# Generated by FakeRAM 2.0
VERSION 5.7 ;
BUSBITCHARS "[]" ;
PROPERTYDEFINITIONS
  MACRO width INTEGER ;
  MACRO depth INTEGER ;
  MACRO banks INTEGER ;
END PROPERTYDEFINITIONS
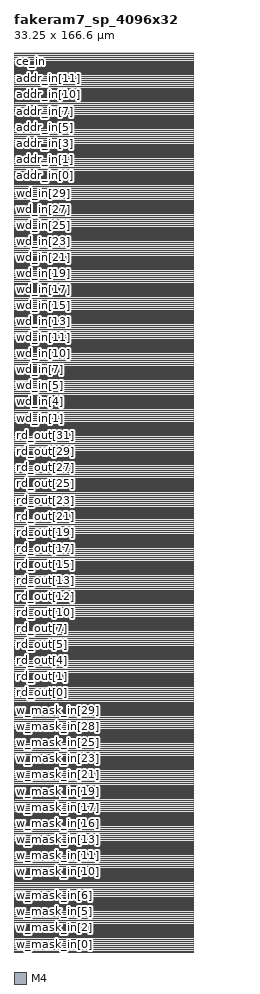
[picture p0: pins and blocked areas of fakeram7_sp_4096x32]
MACRO fakeram7_sp_4096x32
  PROPERTY width 32 ;
  PROPERTY depth 4096 ;
  PROPERTY banks 8 ;
  FOREIGN fakeram7_sp_4096x32 0 0 ;
  SYMMETRY X Y ;
  SIZE 33.250 BY 166.600 ;
  CLASS BLOCK ;
  PIN w_mask_in[0]
    DIRECTION INPUT ;
    USE SIGNAL ;
    SHAPE ABUTMENT ;
    PORT
      LAYER M4 ;
      RECT 0.000 0.048 0.024 0.072 ;
    END
  END w_mask_in[0]
  PIN w_mask_in[1]
    DIRECTION INPUT ;
    USE SIGNAL ;
    SHAPE ABUTMENT ;
    PORT
      LAYER M4 ;
      RECT 0.000 1.536 0.024 1.560 ;
    END
  END w_mask_in[1]
  PIN w_mask_in[2]
    DIRECTION INPUT ;
    USE SIGNAL ;
    SHAPE ABUTMENT ;
    PORT
      LAYER M4 ;
      RECT 0.000 3.024 0.024 3.048 ;
    END
  END w_mask_in[2]
  PIN w_mask_in[3]
    DIRECTION INPUT ;
    USE SIGNAL ;
    SHAPE ABUTMENT ;
    PORT
      LAYER M4 ;
      RECT 0.000 4.512 0.024 4.536 ;
    END
  END w_mask_in[3]
  PIN w_mask_in[4]
    DIRECTION INPUT ;
    USE SIGNAL ;
    SHAPE ABUTMENT ;
    PORT
      LAYER M4 ;
      RECT 0.000 6.000 0.024 6.024 ;
    END
  END w_mask_in[4]
  PIN w_mask_in[5]
    DIRECTION INPUT ;
    USE SIGNAL ;
    SHAPE ABUTMENT ;
    PORT
      LAYER M4 ;
      RECT 0.000 7.488 0.024 7.512 ;
    END
  END w_mask_in[5]
  PIN w_mask_in[6]
    DIRECTION INPUT ;
    USE SIGNAL ;
    SHAPE ABUTMENT ;
    PORT
      LAYER M4 ;
      RECT 0.000 8.976 0.024 9.000 ;
    END
  END w_mask_in[6]
  PIN w_mask_in[7]
    DIRECTION INPUT ;
    USE SIGNAL ;
    SHAPE ABUTMENT ;
    PORT
      LAYER M4 ;
      RECT 0.000 10.464 0.024 10.488 ;
    END
  END w_mask_in[7]
  PIN w_mask_in[8]
    DIRECTION INPUT ;
    USE SIGNAL ;
    SHAPE ABUTMENT ;
    PORT
      LAYER M4 ;
      RECT 0.000 11.952 0.024 11.976 ;
    END
  END w_mask_in[8]
  PIN w_mask_in[9]
    DIRECTION INPUT ;
    USE SIGNAL ;
    SHAPE ABUTMENT ;
    PORT
      LAYER M4 ;
      RECT 0.000 13.440 0.024 13.464 ;
    END
  END w_mask_in[9]
  PIN w_mask_in[10]
    DIRECTION INPUT ;
    USE SIGNAL ;
    SHAPE ABUTMENT ;
    PORT
      LAYER M4 ;
      RECT 0.000 14.928 0.024 14.952 ;
    END
  END w_mask_in[10]
  PIN w_mask_in[11]
    DIRECTION INPUT ;
    USE SIGNAL ;
    SHAPE ABUTMENT ;
    PORT
      LAYER M4 ;
      RECT 0.000 16.416 0.024 16.440 ;
    END
  END w_mask_in[11]
  PIN w_mask_in[12]
    DIRECTION INPUT ;
    USE SIGNAL ;
    SHAPE ABUTMENT ;
    PORT
      LAYER M4 ;
      RECT 0.000 17.904 0.024 17.928 ;
    END
  END w_mask_in[12]
  PIN w_mask_in[13]
    DIRECTION INPUT ;
    USE SIGNAL ;
    SHAPE ABUTMENT ;
    PORT
      LAYER M4 ;
      RECT 0.000 19.392 0.024 19.416 ;
    END
  END w_mask_in[13]
  PIN w_mask_in[14]
    DIRECTION INPUT ;
    USE SIGNAL ;
    SHAPE ABUTMENT ;
    PORT
      LAYER M4 ;
      RECT 0.000 20.880 0.024 20.904 ;
    END
  END w_mask_in[14]
  PIN w_mask_in[15]
    DIRECTION INPUT ;
    USE SIGNAL ;
    SHAPE ABUTMENT ;
    PORT
      LAYER M4 ;
      RECT 0.000 22.368 0.024 22.392 ;
    END
  END w_mask_in[15]
  PIN w_mask_in[16]
    DIRECTION INPUT ;
    USE SIGNAL ;
    SHAPE ABUTMENT ;
    PORT
      LAYER M4 ;
      RECT 0.000 23.856 0.024 23.880 ;
    END
  END w_mask_in[16]
  PIN w_mask_in[17]
    DIRECTION INPUT ;
    USE SIGNAL ;
    SHAPE ABUTMENT ;
    PORT
      LAYER M4 ;
      RECT 0.000 25.344 0.024 25.368 ;
    END
  END w_mask_in[17]
  PIN w_mask_in[18]
    DIRECTION INPUT ;
    USE SIGNAL ;
    SHAPE ABUTMENT ;
    PORT
      LAYER M4 ;
      RECT 0.000 26.832 0.024 26.856 ;
    END
  END w_mask_in[18]
  PIN w_mask_in[19]
    DIRECTION INPUT ;
    USE SIGNAL ;
    SHAPE ABUTMENT ;
    PORT
      LAYER M4 ;
      RECT 0.000 28.320 0.024 28.344 ;
    END
  END w_mask_in[19]
  PIN w_mask_in[20]
    DIRECTION INPUT ;
    USE SIGNAL ;
    SHAPE ABUTMENT ;
    PORT
      LAYER M4 ;
      RECT 0.000 29.808 0.024 29.832 ;
    END
  END w_mask_in[20]
  PIN w_mask_in[21]
    DIRECTION INPUT ;
    USE SIGNAL ;
    SHAPE ABUTMENT ;
    PORT
      LAYER M4 ;
      RECT 0.000 31.296 0.024 31.320 ;
    END
  END w_mask_in[21]
  PIN w_mask_in[22]
    DIRECTION INPUT ;
    USE SIGNAL ;
    SHAPE ABUTMENT ;
    PORT
      LAYER M4 ;
      RECT 0.000 32.784 0.024 32.808 ;
    END
  END w_mask_in[22]
  PIN w_mask_in[23]
    DIRECTION INPUT ;
    USE SIGNAL ;
    SHAPE ABUTMENT ;
    PORT
      LAYER M4 ;
      RECT 0.000 34.272 0.024 34.296 ;
    END
  END w_mask_in[23]
  PIN w_mask_in[24]
    DIRECTION INPUT ;
    USE SIGNAL ;
    SHAPE ABUTMENT ;
    PORT
      LAYER M4 ;
      RECT 0.000 35.760 0.024 35.784 ;
    END
  END w_mask_in[24]
  PIN w_mask_in[25]
    DIRECTION INPUT ;
    USE SIGNAL ;
    SHAPE ABUTMENT ;
    PORT
      LAYER M4 ;
      RECT 0.000 37.248 0.024 37.272 ;
    END
  END w_mask_in[25]
  PIN w_mask_in[26]
    DIRECTION INPUT ;
    USE SIGNAL ;
    SHAPE ABUTMENT ;
    PORT
      LAYER M4 ;
      RECT 0.000 38.736 0.024 38.760 ;
    END
  END w_mask_in[26]
  PIN w_mask_in[27]
    DIRECTION INPUT ;
    USE SIGNAL ;
    SHAPE ABUTMENT ;
    PORT
      LAYER M4 ;
      RECT 0.000 40.224 0.024 40.248 ;
    END
  END w_mask_in[27]
  PIN w_mask_in[28]
    DIRECTION INPUT ;
    USE SIGNAL ;
    SHAPE ABUTMENT ;
    PORT
      LAYER M4 ;
      RECT 0.000 41.712 0.024 41.736 ;
    END
  END w_mask_in[28]
  PIN w_mask_in[29]
    DIRECTION INPUT ;
    USE SIGNAL ;
    SHAPE ABUTMENT ;
    PORT
      LAYER M4 ;
      RECT 0.000 43.200 0.024 43.224 ;
    END
  END w_mask_in[29]
  PIN w_mask_in[30]
    DIRECTION INPUT ;
    USE SIGNAL ;
    SHAPE ABUTMENT ;
    PORT
      LAYER M4 ;
      RECT 0.000 44.688 0.024 44.712 ;
    END
  END w_mask_in[30]
  PIN w_mask_in[31]
    DIRECTION INPUT ;
    USE SIGNAL ;
    SHAPE ABUTMENT ;
    PORT
      LAYER M4 ;
      RECT 0.000 46.176 0.024 46.200 ;
    END
  END w_mask_in[31]
  PIN rd_out[0]
    DIRECTION OUTPUT ;
    USE SIGNAL ;
    SHAPE ABUTMENT ;
    PORT
      LAYER M4 ;
      RECT 0.000 47.952 0.024 47.976 ;
    END
  END rd_out[0]
  PIN rd_out[1]
    DIRECTION OUTPUT ;
    USE SIGNAL ;
    SHAPE ABUTMENT ;
    PORT
      LAYER M4 ;
      RECT 0.000 49.440 0.024 49.464 ;
    END
  END rd_out[1]
  PIN rd_out[2]
    DIRECTION OUTPUT ;
    USE SIGNAL ;
    SHAPE ABUTMENT ;
    PORT
      LAYER M4 ;
      RECT 0.000 50.928 0.024 50.952 ;
    END
  END rd_out[2]
  PIN rd_out[3]
    DIRECTION OUTPUT ;
    USE SIGNAL ;
    SHAPE ABUTMENT ;
    PORT
      LAYER M4 ;
      RECT 0.000 52.416 0.024 52.440 ;
    END
  END rd_out[3]
  PIN rd_out[4]
    DIRECTION OUTPUT ;
    USE SIGNAL ;
    SHAPE ABUTMENT ;
    PORT
      LAYER M4 ;
      RECT 0.000 53.904 0.024 53.928 ;
    END
  END rd_out[4]
  PIN rd_out[5]
    DIRECTION OUTPUT ;
    USE SIGNAL ;
    SHAPE ABUTMENT ;
    PORT
      LAYER M4 ;
      RECT 0.000 55.392 0.024 55.416 ;
    END
  END rd_out[5]
  PIN rd_out[6]
    DIRECTION OUTPUT ;
    USE SIGNAL ;
    SHAPE ABUTMENT ;
    PORT
      LAYER M4 ;
      RECT 0.000 56.880 0.024 56.904 ;
    END
  END rd_out[6]
  PIN rd_out[7]
    DIRECTION OUTPUT ;
    USE SIGNAL ;
    SHAPE ABUTMENT ;
    PORT
      LAYER M4 ;
      RECT 0.000 58.368 0.024 58.392 ;
    END
  END rd_out[7]
  PIN rd_out[8]
    DIRECTION OUTPUT ;
    USE SIGNAL ;
    SHAPE ABUTMENT ;
    PORT
      LAYER M4 ;
      RECT 0.000 59.856 0.024 59.880 ;
    END
  END rd_out[8]
  PIN rd_out[9]
    DIRECTION OUTPUT ;
    USE SIGNAL ;
    SHAPE ABUTMENT ;
    PORT
      LAYER M4 ;
      RECT 0.000 61.344 0.024 61.368 ;
    END
  END rd_out[9]
  PIN rd_out[10]
    DIRECTION OUTPUT ;
    USE SIGNAL ;
    SHAPE ABUTMENT ;
    PORT
      LAYER M4 ;
      RECT 0.000 62.832 0.024 62.856 ;
    END
  END rd_out[10]
  PIN rd_out[11]
    DIRECTION OUTPUT ;
    USE SIGNAL ;
    SHAPE ABUTMENT ;
    PORT
      LAYER M4 ;
      RECT 0.000 64.320 0.024 64.344 ;
    END
  END rd_out[11]
  PIN rd_out[12]
    DIRECTION OUTPUT ;
    USE SIGNAL ;
    SHAPE ABUTMENT ;
    PORT
      LAYER M4 ;
      RECT 0.000 65.808 0.024 65.832 ;
    END
  END rd_out[12]
  PIN rd_out[13]
    DIRECTION OUTPUT ;
    USE SIGNAL ;
    SHAPE ABUTMENT ;
    PORT
      LAYER M4 ;
      RECT 0.000 67.296 0.024 67.320 ;
    END
  END rd_out[13]
  PIN rd_out[14]
    DIRECTION OUTPUT ;
    USE SIGNAL ;
    SHAPE ABUTMENT ;
    PORT
      LAYER M4 ;
      RECT 0.000 68.784 0.024 68.808 ;
    END
  END rd_out[14]
  PIN rd_out[15]
    DIRECTION OUTPUT ;
    USE SIGNAL ;
    SHAPE ABUTMENT ;
    PORT
      LAYER M4 ;
      RECT 0.000 70.272 0.024 70.296 ;
    END
  END rd_out[15]
  PIN rd_out[16]
    DIRECTION OUTPUT ;
    USE SIGNAL ;
    SHAPE ABUTMENT ;
    PORT
      LAYER M4 ;
      RECT 0.000 71.760 0.024 71.784 ;
    END
  END rd_out[16]
  PIN rd_out[17]
    DIRECTION OUTPUT ;
    USE SIGNAL ;
    SHAPE ABUTMENT ;
    PORT
      LAYER M4 ;
      RECT 0.000 73.248 0.024 73.272 ;
    END
  END rd_out[17]
  PIN rd_out[18]
    DIRECTION OUTPUT ;
    USE SIGNAL ;
    SHAPE ABUTMENT ;
    PORT
      LAYER M4 ;
      RECT 0.000 74.736 0.024 74.760 ;
    END
  END rd_out[18]
  PIN rd_out[19]
    DIRECTION OUTPUT ;
    USE SIGNAL ;
    SHAPE ABUTMENT ;
    PORT
      LAYER M4 ;
      RECT 0.000 76.224 0.024 76.248 ;
    END
  END rd_out[19]
  PIN rd_out[20]
    DIRECTION OUTPUT ;
    USE SIGNAL ;
    SHAPE ABUTMENT ;
    PORT
      LAYER M4 ;
      RECT 0.000 77.712 0.024 77.736 ;
    END
  END rd_out[20]
  PIN rd_out[21]
    DIRECTION OUTPUT ;
    USE SIGNAL ;
    SHAPE ABUTMENT ;
    PORT
      LAYER M4 ;
      RECT 0.000 79.200 0.024 79.224 ;
    END
  END rd_out[21]
  PIN rd_out[22]
    DIRECTION OUTPUT ;
    USE SIGNAL ;
    SHAPE ABUTMENT ;
    PORT
      LAYER M4 ;
      RECT 0.000 80.688 0.024 80.712 ;
    END
  END rd_out[22]
  PIN rd_out[23]
    DIRECTION OUTPUT ;
    USE SIGNAL ;
    SHAPE ABUTMENT ;
    PORT
      LAYER M4 ;
      RECT 0.000 82.176 0.024 82.200 ;
    END
  END rd_out[23]
  PIN rd_out[24]
    DIRECTION OUTPUT ;
    USE SIGNAL ;
    SHAPE ABUTMENT ;
    PORT
      LAYER M4 ;
      RECT 0.000 83.664 0.024 83.688 ;
    END
  END rd_out[24]
  PIN rd_out[25]
    DIRECTION OUTPUT ;
    USE SIGNAL ;
    SHAPE ABUTMENT ;
    PORT
      LAYER M4 ;
      RECT 0.000 85.152 0.024 85.176 ;
    END
  END rd_out[25]
  PIN rd_out[26]
    DIRECTION OUTPUT ;
    USE SIGNAL ;
    SHAPE ABUTMENT ;
    PORT
      LAYER M4 ;
      RECT 0.000 86.640 0.024 86.664 ;
    END
  END rd_out[26]
  PIN rd_out[27]
    DIRECTION OUTPUT ;
    USE SIGNAL ;
    SHAPE ABUTMENT ;
    PORT
      LAYER M4 ;
      RECT 0.000 88.128 0.024 88.152 ;
    END
  END rd_out[27]
  PIN rd_out[28]
    DIRECTION OUTPUT ;
    USE SIGNAL ;
    SHAPE ABUTMENT ;
    PORT
      LAYER M4 ;
      RECT 0.000 89.616 0.024 89.640 ;
    END
  END rd_out[28]
  PIN rd_out[29]
    DIRECTION OUTPUT ;
    USE SIGNAL ;
    SHAPE ABUTMENT ;
    PORT
      LAYER M4 ;
      RECT 0.000 91.104 0.024 91.128 ;
    END
  END rd_out[29]
  PIN rd_out[30]
    DIRECTION OUTPUT ;
    USE SIGNAL ;
    SHAPE ABUTMENT ;
    PORT
      LAYER M4 ;
      RECT 0.000 92.592 0.024 92.616 ;
    END
  END rd_out[30]
  PIN rd_out[31]
    DIRECTION OUTPUT ;
    USE SIGNAL ;
    SHAPE ABUTMENT ;
    PORT
      LAYER M4 ;
      RECT 0.000 94.080 0.024 94.104 ;
    END
  END rd_out[31]
  PIN wd_in[0]
    DIRECTION INPUT ;
    USE SIGNAL ;
    SHAPE ABUTMENT ;
    PORT
      LAYER M4 ;
      RECT 0.000 95.856 0.024 95.880 ;
    END
  END wd_in[0]
  PIN wd_in[1]
    DIRECTION INPUT ;
    USE SIGNAL ;
    SHAPE ABUTMENT ;
    PORT
      LAYER M4 ;
      RECT 0.000 97.344 0.024 97.368 ;
    END
  END wd_in[1]
  PIN wd_in[2]
    DIRECTION INPUT ;
    USE SIGNAL ;
    SHAPE ABUTMENT ;
    PORT
      LAYER M4 ;
      RECT 0.000 98.832 0.024 98.856 ;
    END
  END wd_in[2]
  PIN wd_in[3]
    DIRECTION INPUT ;
    USE SIGNAL ;
    SHAPE ABUTMENT ;
    PORT
      LAYER M4 ;
      RECT 0.000 100.320 0.024 100.344 ;
    END
  END wd_in[3]
  PIN wd_in[4]
    DIRECTION INPUT ;
    USE SIGNAL ;
    SHAPE ABUTMENT ;
    PORT
      LAYER M4 ;
      RECT 0.000 101.808 0.024 101.832 ;
    END
  END wd_in[4]
  PIN wd_in[5]
    DIRECTION INPUT ;
    USE SIGNAL ;
    SHAPE ABUTMENT ;
    PORT
      LAYER M4 ;
      RECT 0.000 103.296 0.024 103.320 ;
    END
  END wd_in[5]
  PIN wd_in[6]
    DIRECTION INPUT ;
    USE SIGNAL ;
    SHAPE ABUTMENT ;
    PORT
      LAYER M4 ;
      RECT 0.000 104.784 0.024 104.808 ;
    END
  END wd_in[6]
  PIN wd_in[7]
    DIRECTION INPUT ;
    USE SIGNAL ;
    SHAPE ABUTMENT ;
    PORT
      LAYER M4 ;
      RECT 0.000 106.272 0.024 106.296 ;
    END
  END wd_in[7]
  PIN wd_in[8]
    DIRECTION INPUT ;
    USE SIGNAL ;
    SHAPE ABUTMENT ;
    PORT
      LAYER M4 ;
      RECT 0.000 107.760 0.024 107.784 ;
    END
  END wd_in[8]
  PIN wd_in[9]
    DIRECTION INPUT ;
    USE SIGNAL ;
    SHAPE ABUTMENT ;
    PORT
      LAYER M4 ;
      RECT 0.000 109.248 0.024 109.272 ;
    END
  END wd_in[9]
  PIN wd_in[10]
    DIRECTION INPUT ;
    USE SIGNAL ;
    SHAPE ABUTMENT ;
    PORT
      LAYER M4 ;
      RECT 0.000 110.736 0.024 110.760 ;
    END
  END wd_in[10]
  PIN wd_in[11]
    DIRECTION INPUT ;
    USE SIGNAL ;
    SHAPE ABUTMENT ;
    PORT
      LAYER M4 ;
      RECT 0.000 112.224 0.024 112.248 ;
    END
  END wd_in[11]
  PIN wd_in[12]
    DIRECTION INPUT ;
    USE SIGNAL ;
    SHAPE ABUTMENT ;
    PORT
      LAYER M4 ;
      RECT 0.000 113.712 0.024 113.736 ;
    END
  END wd_in[12]
  PIN wd_in[13]
    DIRECTION INPUT ;
    USE SIGNAL ;
    SHAPE ABUTMENT ;
    PORT
      LAYER M4 ;
      RECT 0.000 115.200 0.024 115.224 ;
    END
  END wd_in[13]
  PIN wd_in[14]
    DIRECTION INPUT ;
    USE SIGNAL ;
    SHAPE ABUTMENT ;
    PORT
      LAYER M4 ;
      RECT 0.000 116.688 0.024 116.712 ;
    END
  END wd_in[14]
  PIN wd_in[15]
    DIRECTION INPUT ;
    USE SIGNAL ;
    SHAPE ABUTMENT ;
    PORT
      LAYER M4 ;
      RECT 0.000 118.176 0.024 118.200 ;
    END
  END wd_in[15]
  PIN wd_in[16]
    DIRECTION INPUT ;
    USE SIGNAL ;
    SHAPE ABUTMENT ;
    PORT
      LAYER M4 ;
      RECT 0.000 119.664 0.024 119.688 ;
    END
  END wd_in[16]
  PIN wd_in[17]
    DIRECTION INPUT ;
    USE SIGNAL ;
    SHAPE ABUTMENT ;
    PORT
      LAYER M4 ;
      RECT 0.000 121.152 0.024 121.176 ;
    END
  END wd_in[17]
  PIN wd_in[18]
    DIRECTION INPUT ;
    USE SIGNAL ;
    SHAPE ABUTMENT ;
    PORT
      LAYER M4 ;
      RECT 0.000 122.640 0.024 122.664 ;
    END
  END wd_in[18]
  PIN wd_in[19]
    DIRECTION INPUT ;
    USE SIGNAL ;
    SHAPE ABUTMENT ;
    PORT
      LAYER M4 ;
      RECT 0.000 124.128 0.024 124.152 ;
    END
  END wd_in[19]
  PIN wd_in[20]
    DIRECTION INPUT ;
    USE SIGNAL ;
    SHAPE ABUTMENT ;
    PORT
      LAYER M4 ;
      RECT 0.000 125.616 0.024 125.640 ;
    END
  END wd_in[20]
  PIN wd_in[21]
    DIRECTION INPUT ;
    USE SIGNAL ;
    SHAPE ABUTMENT ;
    PORT
      LAYER M4 ;
      RECT 0.000 127.104 0.024 127.128 ;
    END
  END wd_in[21]
  PIN wd_in[22]
    DIRECTION INPUT ;
    USE SIGNAL ;
    SHAPE ABUTMENT ;
    PORT
      LAYER M4 ;
      RECT 0.000 128.592 0.024 128.616 ;
    END
  END wd_in[22]
  PIN wd_in[23]
    DIRECTION INPUT ;
    USE SIGNAL ;
    SHAPE ABUTMENT ;
    PORT
      LAYER M4 ;
      RECT 0.000 130.080 0.024 130.104 ;
    END
  END wd_in[23]
  PIN wd_in[24]
    DIRECTION INPUT ;
    USE SIGNAL ;
    SHAPE ABUTMENT ;
    PORT
      LAYER M4 ;
      RECT 0.000 131.568 0.024 131.592 ;
    END
  END wd_in[24]
  PIN wd_in[25]
    DIRECTION INPUT ;
    USE SIGNAL ;
    SHAPE ABUTMENT ;
    PORT
      LAYER M4 ;
      RECT 0.000 133.056 0.024 133.080 ;
    END
  END wd_in[25]
  PIN wd_in[26]
    DIRECTION INPUT ;
    USE SIGNAL ;
    SHAPE ABUTMENT ;
    PORT
      LAYER M4 ;
      RECT 0.000 134.544 0.024 134.568 ;
    END
  END wd_in[26]
  PIN wd_in[27]
    DIRECTION INPUT ;
    USE SIGNAL ;
    SHAPE ABUTMENT ;
    PORT
      LAYER M4 ;
      RECT 0.000 136.032 0.024 136.056 ;
    END
  END wd_in[27]
  PIN wd_in[28]
    DIRECTION INPUT ;
    USE SIGNAL ;
    SHAPE ABUTMENT ;
    PORT
      LAYER M4 ;
      RECT 0.000 137.520 0.024 137.544 ;
    END
  END wd_in[28]
  PIN wd_in[29]
    DIRECTION INPUT ;
    USE SIGNAL ;
    SHAPE ABUTMENT ;
    PORT
      LAYER M4 ;
      RECT 0.000 139.008 0.024 139.032 ;
    END
  END wd_in[29]
  PIN wd_in[30]
    DIRECTION INPUT ;
    USE SIGNAL ;
    SHAPE ABUTMENT ;
    PORT
      LAYER M4 ;
      RECT 0.000 140.496 0.024 140.520 ;
    END
  END wd_in[30]
  PIN wd_in[31]
    DIRECTION INPUT ;
    USE SIGNAL ;
    SHAPE ABUTMENT ;
    PORT
      LAYER M4 ;
      RECT 0.000 141.984 0.024 142.008 ;
    END
  END wd_in[31]
  PIN addr_in[0]
    DIRECTION INPUT ;
    USE SIGNAL ;
    SHAPE ABUTMENT ;
    PORT
      LAYER M4 ;
      RECT 0.000 143.760 0.024 143.784 ;
    END
  END addr_in[0]
  PIN addr_in[1]
    DIRECTION INPUT ;
    USE SIGNAL ;
    SHAPE ABUTMENT ;
    PORT
      LAYER M4 ;
      RECT 0.000 145.248 0.024 145.272 ;
    END
  END addr_in[1]
  PIN addr_in[2]
    DIRECTION INPUT ;
    USE SIGNAL ;
    SHAPE ABUTMENT ;
    PORT
      LAYER M4 ;
      RECT 0.000 146.736 0.024 146.760 ;
    END
  END addr_in[2]
  PIN addr_in[3]
    DIRECTION INPUT ;
    USE SIGNAL ;
    SHAPE ABUTMENT ;
    PORT
      LAYER M4 ;
      RECT 0.000 148.224 0.024 148.248 ;
    END
  END addr_in[3]
  PIN addr_in[4]
    DIRECTION INPUT ;
    USE SIGNAL ;
    SHAPE ABUTMENT ;
    PORT
      LAYER M4 ;
      RECT 0.000 149.712 0.024 149.736 ;
    END
  END addr_in[4]
  PIN addr_in[5]
    DIRECTION INPUT ;
    USE SIGNAL ;
    SHAPE ABUTMENT ;
    PORT
      LAYER M4 ;
      RECT 0.000 151.200 0.024 151.224 ;
    END
  END addr_in[5]
  PIN addr_in[6]
    DIRECTION INPUT ;
    USE SIGNAL ;
    SHAPE ABUTMENT ;
    PORT
      LAYER M4 ;
      RECT 0.000 152.688 0.024 152.712 ;
    END
  END addr_in[6]
  PIN addr_in[7]
    DIRECTION INPUT ;
    USE SIGNAL ;
    SHAPE ABUTMENT ;
    PORT
      LAYER M4 ;
      RECT 0.000 154.176 0.024 154.200 ;
    END
  END addr_in[7]
  PIN addr_in[8]
    DIRECTION INPUT ;
    USE SIGNAL ;
    SHAPE ABUTMENT ;
    PORT
      LAYER M4 ;
      RECT 0.000 155.664 0.024 155.688 ;
    END
  END addr_in[8]
  PIN addr_in[9]
    DIRECTION INPUT ;
    USE SIGNAL ;
    SHAPE ABUTMENT ;
    PORT
      LAYER M4 ;
      RECT 0.000 157.152 0.024 157.176 ;
    END
  END addr_in[9]
  PIN addr_in[10]
    DIRECTION INPUT ;
    USE SIGNAL ;
    SHAPE ABUTMENT ;
    PORT
      LAYER M4 ;
      RECT 0.000 158.640 0.024 158.664 ;
    END
  END addr_in[10]
  PIN addr_in[11]
    DIRECTION INPUT ;
    USE SIGNAL ;
    SHAPE ABUTMENT ;
    PORT
      LAYER M4 ;
      RECT 0.000 160.128 0.024 160.152 ;
    END
  END addr_in[11]
  PIN we_in
    DIRECTION INPUT ;
    USE SIGNAL ;
    SHAPE ABUTMENT ;
    PORT
      LAYER M4 ;
      RECT 0.000 161.904 0.024 161.928 ;
    END
  END we_in
  PIN ce_in
    DIRECTION INPUT ;
    USE SIGNAL ;
    SHAPE ABUTMENT ;
    PORT
      LAYER M4 ;
      RECT 0.000 163.392 0.024 163.416 ;
    END
  END ce_in
  PIN clk
    DIRECTION INPUT ;
    USE SIGNAL ;
    SHAPE ABUTMENT ;
    PORT
      LAYER M4 ;
      RECT 0.000 164.880 0.024 164.904 ;
    END
  END clk
  PIN VSS
    DIRECTION INOUT ;
    USE GROUND ;
    PORT
      LAYER M4 ;
      RECT 0.048 0.000 33.202 0.096 ;
      RECT 0.048 0.768 33.202 0.864 ;
      RECT 0.048 1.536 33.202 1.632 ;
      RECT 0.048 2.304 33.202 2.400 ;
      RECT 0.048 3.072 33.202 3.168 ;
      RECT 0.048 3.840 33.202 3.936 ;
      RECT 0.048 4.608 33.202 4.704 ;
      RECT 0.048 5.376 33.202 5.472 ;
      RECT 0.048 6.144 33.202 6.240 ;
      RECT 0.048 6.912 33.202 7.008 ;
      RECT 0.048 7.680 33.202 7.776 ;
      RECT 0.048 8.448 33.202 8.544 ;
      RECT 0.048 9.216 33.202 9.312 ;
      RECT 0.048 9.984 33.202 10.080 ;
      RECT 0.048 10.752 33.202 10.848 ;
      RECT 0.048 11.520 33.202 11.616 ;
      RECT 0.048 12.288 33.202 12.384 ;
      RECT 0.048 13.056 33.202 13.152 ;
      RECT 0.048 13.824 33.202 13.920 ;
      RECT 0.048 14.592 33.202 14.688 ;
      RECT 0.048 15.360 33.202 15.456 ;
      RECT 0.048 16.128 33.202 16.224 ;
      RECT 0.048 16.896 33.202 16.992 ;
      RECT 0.048 17.664 33.202 17.760 ;
      RECT 0.048 18.432 33.202 18.528 ;
      RECT 0.048 19.200 33.202 19.296 ;
      RECT 0.048 19.968 33.202 20.064 ;
      RECT 0.048 20.736 33.202 20.832 ;
      RECT 0.048 21.504 33.202 21.600 ;
      RECT 0.048 22.272 33.202 22.368 ;
      RECT 0.048 23.040 33.202 23.136 ;
      RECT 0.048 23.808 33.202 23.904 ;
      RECT 0.048 24.576 33.202 24.672 ;
      RECT 0.048 25.344 33.202 25.440 ;
      RECT 0.048 26.112 33.202 26.208 ;
      RECT 0.048 26.880 33.202 26.976 ;
      RECT 0.048 27.648 33.202 27.744 ;
      RECT 0.048 28.416 33.202 28.512 ;
      RECT 0.048 29.184 33.202 29.280 ;
      RECT 0.048 29.952 33.202 30.048 ;
      RECT 0.048 30.720 33.202 30.816 ;
      RECT 0.048 31.488 33.202 31.584 ;
      RECT 0.048 32.256 33.202 32.352 ;
      RECT 0.048 33.024 33.202 33.120 ;
      RECT 0.048 33.792 33.202 33.888 ;
      RECT 0.048 34.560 33.202 34.656 ;
      RECT 0.048 35.328 33.202 35.424 ;
      RECT 0.048 36.096 33.202 36.192 ;
      RECT 0.048 36.864 33.202 36.960 ;
      RECT 0.048 37.632 33.202 37.728 ;
      RECT 0.048 38.400 33.202 38.496 ;
      RECT 0.048 39.168 33.202 39.264 ;
      RECT 0.048 39.936 33.202 40.032 ;
      RECT 0.048 40.704 33.202 40.800 ;
      RECT 0.048 41.472 33.202 41.568 ;
      RECT 0.048 42.240 33.202 42.336 ;
      RECT 0.048 43.008 33.202 43.104 ;
      RECT 0.048 43.776 33.202 43.872 ;
      RECT 0.048 44.544 33.202 44.640 ;
      RECT 0.048 45.312 33.202 45.408 ;
      RECT 0.048 46.080 33.202 46.176 ;
      RECT 0.048 46.848 33.202 46.944 ;
      RECT 0.048 47.616 33.202 47.712 ;
      RECT 0.048 48.384 33.202 48.480 ;
      RECT 0.048 49.152 33.202 49.248 ;
      RECT 0.048 49.920 33.202 50.016 ;
      RECT 0.048 50.688 33.202 50.784 ;
      RECT 0.048 51.456 33.202 51.552 ;
      RECT 0.048 52.224 33.202 52.320 ;
      RECT 0.048 52.992 33.202 53.088 ;
      RECT 0.048 53.760 33.202 53.856 ;
      RECT 0.048 54.528 33.202 54.624 ;
      RECT 0.048 55.296 33.202 55.392 ;
      RECT 0.048 56.064 33.202 56.160 ;
      RECT 0.048 56.832 33.202 56.928 ;
      RECT 0.048 57.600 33.202 57.696 ;
      RECT 0.048 58.368 33.202 58.464 ;
      RECT 0.048 59.136 33.202 59.232 ;
      RECT 0.048 59.904 33.202 60.000 ;
      RECT 0.048 60.672 33.202 60.768 ;
      RECT 0.048 61.440 33.202 61.536 ;
      RECT 0.048 62.208 33.202 62.304 ;
      RECT 0.048 62.976 33.202 63.072 ;
      RECT 0.048 63.744 33.202 63.840 ;
      RECT 0.048 64.512 33.202 64.608 ;
      RECT 0.048 65.280 33.202 65.376 ;
      RECT 0.048 66.048 33.202 66.144 ;
      RECT 0.048 66.816 33.202 66.912 ;
      RECT 0.048 67.584 33.202 67.680 ;
      RECT 0.048 68.352 33.202 68.448 ;
      RECT 0.048 69.120 33.202 69.216 ;
      RECT 0.048 69.888 33.202 69.984 ;
      RECT 0.048 70.656 33.202 70.752 ;
      RECT 0.048 71.424 33.202 71.520 ;
      RECT 0.048 72.192 33.202 72.288 ;
      RECT 0.048 72.960 33.202 73.056 ;
      RECT 0.048 73.728 33.202 73.824 ;
      RECT 0.048 74.496 33.202 74.592 ;
      RECT 0.048 75.264 33.202 75.360 ;
      RECT 0.048 76.032 33.202 76.128 ;
      RECT 0.048 76.800 33.202 76.896 ;
      RECT 0.048 77.568 33.202 77.664 ;
      RECT 0.048 78.336 33.202 78.432 ;
      RECT 0.048 79.104 33.202 79.200 ;
      RECT 0.048 79.872 33.202 79.968 ;
      RECT 0.048 80.640 33.202 80.736 ;
      RECT 0.048 81.408 33.202 81.504 ;
      RECT 0.048 82.176 33.202 82.272 ;
      RECT 0.048 82.944 33.202 83.040 ;
      RECT 0.048 83.712 33.202 83.808 ;
      RECT 0.048 84.480 33.202 84.576 ;
      RECT 0.048 85.248 33.202 85.344 ;
      RECT 0.048 86.016 33.202 86.112 ;
      RECT 0.048 86.784 33.202 86.880 ;
      RECT 0.048 87.552 33.202 87.648 ;
      RECT 0.048 88.320 33.202 88.416 ;
      RECT 0.048 89.088 33.202 89.184 ;
      RECT 0.048 89.856 33.202 89.952 ;
      RECT 0.048 90.624 33.202 90.720 ;
      RECT 0.048 91.392 33.202 91.488 ;
      RECT 0.048 92.160 33.202 92.256 ;
      RECT 0.048 92.928 33.202 93.024 ;
      RECT 0.048 93.696 33.202 93.792 ;
      RECT 0.048 94.464 33.202 94.560 ;
      RECT 0.048 95.232 33.202 95.328 ;
      RECT 0.048 96.000 33.202 96.096 ;
      RECT 0.048 96.768 33.202 96.864 ;
      RECT 0.048 97.536 33.202 97.632 ;
      RECT 0.048 98.304 33.202 98.400 ;
      RECT 0.048 99.072 33.202 99.168 ;
      RECT 0.048 99.840 33.202 99.936 ;
      RECT 0.048 100.608 33.202 100.704 ;
      RECT 0.048 101.376 33.202 101.472 ;
      RECT 0.048 102.144 33.202 102.240 ;
      RECT 0.048 102.912 33.202 103.008 ;
      RECT 0.048 103.680 33.202 103.776 ;
      RECT 0.048 104.448 33.202 104.544 ;
      RECT 0.048 105.216 33.202 105.312 ;
      RECT 0.048 105.984 33.202 106.080 ;
      RECT 0.048 106.752 33.202 106.848 ;
      RECT 0.048 107.520 33.202 107.616 ;
      RECT 0.048 108.288 33.202 108.384 ;
      RECT 0.048 109.056 33.202 109.152 ;
      RECT 0.048 109.824 33.202 109.920 ;
      RECT 0.048 110.592 33.202 110.688 ;
      RECT 0.048 111.360 33.202 111.456 ;
      RECT 0.048 112.128 33.202 112.224 ;
      RECT 0.048 112.896 33.202 112.992 ;
      RECT 0.048 113.664 33.202 113.760 ;
      RECT 0.048 114.432 33.202 114.528 ;
      RECT 0.048 115.200 33.202 115.296 ;
      RECT 0.048 115.968 33.202 116.064 ;
      RECT 0.048 116.736 33.202 116.832 ;
      RECT 0.048 117.504 33.202 117.600 ;
      RECT 0.048 118.272 33.202 118.368 ;
      RECT 0.048 119.040 33.202 119.136 ;
      RECT 0.048 119.808 33.202 119.904 ;
      RECT 0.048 120.576 33.202 120.672 ;
      RECT 0.048 121.344 33.202 121.440 ;
      RECT 0.048 122.112 33.202 122.208 ;
      RECT 0.048 122.880 33.202 122.976 ;
      RECT 0.048 123.648 33.202 123.744 ;
      RECT 0.048 124.416 33.202 124.512 ;
      RECT 0.048 125.184 33.202 125.280 ;
      RECT 0.048 125.952 33.202 126.048 ;
      RECT 0.048 126.720 33.202 126.816 ;
      RECT 0.048 127.488 33.202 127.584 ;
      RECT 0.048 128.256 33.202 128.352 ;
      RECT 0.048 129.024 33.202 129.120 ;
      RECT 0.048 129.792 33.202 129.888 ;
      RECT 0.048 130.560 33.202 130.656 ;
      RECT 0.048 131.328 33.202 131.424 ;
      RECT 0.048 132.096 33.202 132.192 ;
      RECT 0.048 132.864 33.202 132.960 ;
      RECT 0.048 133.632 33.202 133.728 ;
      RECT 0.048 134.400 33.202 134.496 ;
      RECT 0.048 135.168 33.202 135.264 ;
      RECT 0.048 135.936 33.202 136.032 ;
      RECT 0.048 136.704 33.202 136.800 ;
      RECT 0.048 137.472 33.202 137.568 ;
      RECT 0.048 138.240 33.202 138.336 ;
      RECT 0.048 139.008 33.202 139.104 ;
      RECT 0.048 139.776 33.202 139.872 ;
      RECT 0.048 140.544 33.202 140.640 ;
      RECT 0.048 141.312 33.202 141.408 ;
      RECT 0.048 142.080 33.202 142.176 ;
      RECT 0.048 142.848 33.202 142.944 ;
      RECT 0.048 143.616 33.202 143.712 ;
      RECT 0.048 144.384 33.202 144.480 ;
      RECT 0.048 145.152 33.202 145.248 ;
      RECT 0.048 145.920 33.202 146.016 ;
      RECT 0.048 146.688 33.202 146.784 ;
      RECT 0.048 147.456 33.202 147.552 ;
      RECT 0.048 148.224 33.202 148.320 ;
      RECT 0.048 148.992 33.202 149.088 ;
      RECT 0.048 149.760 33.202 149.856 ;
      RECT 0.048 150.528 33.202 150.624 ;
      RECT 0.048 151.296 33.202 151.392 ;
      RECT 0.048 152.064 33.202 152.160 ;
      RECT 0.048 152.832 33.202 152.928 ;
      RECT 0.048 153.600 33.202 153.696 ;
      RECT 0.048 154.368 33.202 154.464 ;
      RECT 0.048 155.136 33.202 155.232 ;
      RECT 0.048 155.904 33.202 156.000 ;
      RECT 0.048 156.672 33.202 156.768 ;
      RECT 0.048 157.440 33.202 157.536 ;
      RECT 0.048 158.208 33.202 158.304 ;
      RECT 0.048 158.976 33.202 159.072 ;
      RECT 0.048 159.744 33.202 159.840 ;
      RECT 0.048 160.512 33.202 160.608 ;
      RECT 0.048 161.280 33.202 161.376 ;
      RECT 0.048 162.048 33.202 162.144 ;
      RECT 0.048 162.816 33.202 162.912 ;
      RECT 0.048 163.584 33.202 163.680 ;
      RECT 0.048 164.352 33.202 164.448 ;
      RECT 0.048 165.120 33.202 165.216 ;
      RECT 0.048 165.888 33.202 165.984 ;
    END
  END VSS
  PIN VDD
    DIRECTION INOUT ;
    USE POWER ;
    PORT
      LAYER M4 ;
      RECT 0.048 0.384 33.202 0.480 ;
      RECT 0.048 1.152 33.202 1.248 ;
      RECT 0.048 1.920 33.202 2.016 ;
      RECT 0.048 2.688 33.202 2.784 ;
      RECT 0.048 3.456 33.202 3.552 ;
      RECT 0.048 4.224 33.202 4.320 ;
      RECT 0.048 4.992 33.202 5.088 ;
      RECT 0.048 5.760 33.202 5.856 ;
      RECT 0.048 6.528 33.202 6.624 ;
      RECT 0.048 7.296 33.202 7.392 ;
      RECT 0.048 8.064 33.202 8.160 ;
      RECT 0.048 8.832 33.202 8.928 ;
      RECT 0.048 9.600 33.202 9.696 ;
      RECT 0.048 10.368 33.202 10.464 ;
      RECT 0.048 11.136 33.202 11.232 ;
      RECT 0.048 11.904 33.202 12.000 ;
      RECT 0.048 12.672 33.202 12.768 ;
      RECT 0.048 13.440 33.202 13.536 ;
      RECT 0.048 14.208 33.202 14.304 ;
      RECT 0.048 14.976 33.202 15.072 ;
      RECT 0.048 15.744 33.202 15.840 ;
      RECT 0.048 16.512 33.202 16.608 ;
      RECT 0.048 17.280 33.202 17.376 ;
      RECT 0.048 18.048 33.202 18.144 ;
      RECT 0.048 18.816 33.202 18.912 ;
      RECT 0.048 19.584 33.202 19.680 ;
      RECT 0.048 20.352 33.202 20.448 ;
      RECT 0.048 21.120 33.202 21.216 ;
      RECT 0.048 21.888 33.202 21.984 ;
      RECT 0.048 22.656 33.202 22.752 ;
      RECT 0.048 23.424 33.202 23.520 ;
      RECT 0.048 24.192 33.202 24.288 ;
      RECT 0.048 24.960 33.202 25.056 ;
      RECT 0.048 25.728 33.202 25.824 ;
      RECT 0.048 26.496 33.202 26.592 ;
      RECT 0.048 27.264 33.202 27.360 ;
      RECT 0.048 28.032 33.202 28.128 ;
      RECT 0.048 28.800 33.202 28.896 ;
      RECT 0.048 29.568 33.202 29.664 ;
      RECT 0.048 30.336 33.202 30.432 ;
      RECT 0.048 31.104 33.202 31.200 ;
      RECT 0.048 31.872 33.202 31.968 ;
      RECT 0.048 32.640 33.202 32.736 ;
      RECT 0.048 33.408 33.202 33.504 ;
      RECT 0.048 34.176 33.202 34.272 ;
      RECT 0.048 34.944 33.202 35.040 ;
      RECT 0.048 35.712 33.202 35.808 ;
      RECT 0.048 36.480 33.202 36.576 ;
      RECT 0.048 37.248 33.202 37.344 ;
      RECT 0.048 38.016 33.202 38.112 ;
      RECT 0.048 38.784 33.202 38.880 ;
      RECT 0.048 39.552 33.202 39.648 ;
      RECT 0.048 40.320 33.202 40.416 ;
      RECT 0.048 41.088 33.202 41.184 ;
      RECT 0.048 41.856 33.202 41.952 ;
      RECT 0.048 42.624 33.202 42.720 ;
      RECT 0.048 43.392 33.202 43.488 ;
      RECT 0.048 44.160 33.202 44.256 ;
      RECT 0.048 44.928 33.202 45.024 ;
      RECT 0.048 45.696 33.202 45.792 ;
      RECT 0.048 46.464 33.202 46.560 ;
      RECT 0.048 47.232 33.202 47.328 ;
      RECT 0.048 48.000 33.202 48.096 ;
      RECT 0.048 48.768 33.202 48.864 ;
      RECT 0.048 49.536 33.202 49.632 ;
      RECT 0.048 50.304 33.202 50.400 ;
      RECT 0.048 51.072 33.202 51.168 ;
      RECT 0.048 51.840 33.202 51.936 ;
      RECT 0.048 52.608 33.202 52.704 ;
      RECT 0.048 53.376 33.202 53.472 ;
      RECT 0.048 54.144 33.202 54.240 ;
      RECT 0.048 54.912 33.202 55.008 ;
      RECT 0.048 55.680 33.202 55.776 ;
      RECT 0.048 56.448 33.202 56.544 ;
      RECT 0.048 57.216 33.202 57.312 ;
      RECT 0.048 57.984 33.202 58.080 ;
      RECT 0.048 58.752 33.202 58.848 ;
      RECT 0.048 59.520 33.202 59.616 ;
      RECT 0.048 60.288 33.202 60.384 ;
      RECT 0.048 61.056 33.202 61.152 ;
      RECT 0.048 61.824 33.202 61.920 ;
      RECT 0.048 62.592 33.202 62.688 ;
      RECT 0.048 63.360 33.202 63.456 ;
      RECT 0.048 64.128 33.202 64.224 ;
      RECT 0.048 64.896 33.202 64.992 ;
      RECT 0.048 65.664 33.202 65.760 ;
      RECT 0.048 66.432 33.202 66.528 ;
      RECT 0.048 67.200 33.202 67.296 ;
      RECT 0.048 67.968 33.202 68.064 ;
      RECT 0.048 68.736 33.202 68.832 ;
      RECT 0.048 69.504 33.202 69.600 ;
      RECT 0.048 70.272 33.202 70.368 ;
      RECT 0.048 71.040 33.202 71.136 ;
      RECT 0.048 71.808 33.202 71.904 ;
      RECT 0.048 72.576 33.202 72.672 ;
      RECT 0.048 73.344 33.202 73.440 ;
      RECT 0.048 74.112 33.202 74.208 ;
      RECT 0.048 74.880 33.202 74.976 ;
      RECT 0.048 75.648 33.202 75.744 ;
      RECT 0.048 76.416 33.202 76.512 ;
      RECT 0.048 77.184 33.202 77.280 ;
      RECT 0.048 77.952 33.202 78.048 ;
      RECT 0.048 78.720 33.202 78.816 ;
      RECT 0.048 79.488 33.202 79.584 ;
      RECT 0.048 80.256 33.202 80.352 ;
      RECT 0.048 81.024 33.202 81.120 ;
      RECT 0.048 81.792 33.202 81.888 ;
      RECT 0.048 82.560 33.202 82.656 ;
      RECT 0.048 83.328 33.202 83.424 ;
      RECT 0.048 84.096 33.202 84.192 ;
      RECT 0.048 84.864 33.202 84.960 ;
      RECT 0.048 85.632 33.202 85.728 ;
      RECT 0.048 86.400 33.202 86.496 ;
      RECT 0.048 87.168 33.202 87.264 ;
      RECT 0.048 87.936 33.202 88.032 ;
      RECT 0.048 88.704 33.202 88.800 ;
      RECT 0.048 89.472 33.202 89.568 ;
      RECT 0.048 90.240 33.202 90.336 ;
      RECT 0.048 91.008 33.202 91.104 ;
      RECT 0.048 91.776 33.202 91.872 ;
      RECT 0.048 92.544 33.202 92.640 ;
      RECT 0.048 93.312 33.202 93.408 ;
      RECT 0.048 94.080 33.202 94.176 ;
      RECT 0.048 94.848 33.202 94.944 ;
      RECT 0.048 95.616 33.202 95.712 ;
      RECT 0.048 96.384 33.202 96.480 ;
      RECT 0.048 97.152 33.202 97.248 ;
      RECT 0.048 97.920 33.202 98.016 ;
      RECT 0.048 98.688 33.202 98.784 ;
      RECT 0.048 99.456 33.202 99.552 ;
      RECT 0.048 100.224 33.202 100.320 ;
      RECT 0.048 100.992 33.202 101.088 ;
      RECT 0.048 101.760 33.202 101.856 ;
      RECT 0.048 102.528 33.202 102.624 ;
      RECT 0.048 103.296 33.202 103.392 ;
      RECT 0.048 104.064 33.202 104.160 ;
      RECT 0.048 104.832 33.202 104.928 ;
      RECT 0.048 105.600 33.202 105.696 ;
      RECT 0.048 106.368 33.202 106.464 ;
      RECT 0.048 107.136 33.202 107.232 ;
      RECT 0.048 107.904 33.202 108.000 ;
      RECT 0.048 108.672 33.202 108.768 ;
      RECT 0.048 109.440 33.202 109.536 ;
      RECT 0.048 110.208 33.202 110.304 ;
      RECT 0.048 110.976 33.202 111.072 ;
      RECT 0.048 111.744 33.202 111.840 ;
      RECT 0.048 112.512 33.202 112.608 ;
      RECT 0.048 113.280 33.202 113.376 ;
      RECT 0.048 114.048 33.202 114.144 ;
      RECT 0.048 114.816 33.202 114.912 ;
      RECT 0.048 115.584 33.202 115.680 ;
      RECT 0.048 116.352 33.202 116.448 ;
      RECT 0.048 117.120 33.202 117.216 ;
      RECT 0.048 117.888 33.202 117.984 ;
      RECT 0.048 118.656 33.202 118.752 ;
      RECT 0.048 119.424 33.202 119.520 ;
      RECT 0.048 120.192 33.202 120.288 ;
      RECT 0.048 120.960 33.202 121.056 ;
      RECT 0.048 121.728 33.202 121.824 ;
      RECT 0.048 122.496 33.202 122.592 ;
      RECT 0.048 123.264 33.202 123.360 ;
      RECT 0.048 124.032 33.202 124.128 ;
      RECT 0.048 124.800 33.202 124.896 ;
      RECT 0.048 125.568 33.202 125.664 ;
      RECT 0.048 126.336 33.202 126.432 ;
      RECT 0.048 127.104 33.202 127.200 ;
      RECT 0.048 127.872 33.202 127.968 ;
      RECT 0.048 128.640 33.202 128.736 ;
      RECT 0.048 129.408 33.202 129.504 ;
      RECT 0.048 130.176 33.202 130.272 ;
      RECT 0.048 130.944 33.202 131.040 ;
      RECT 0.048 131.712 33.202 131.808 ;
      RECT 0.048 132.480 33.202 132.576 ;
      RECT 0.048 133.248 33.202 133.344 ;
      RECT 0.048 134.016 33.202 134.112 ;
      RECT 0.048 134.784 33.202 134.880 ;
      RECT 0.048 135.552 33.202 135.648 ;
      RECT 0.048 136.320 33.202 136.416 ;
      RECT 0.048 137.088 33.202 137.184 ;
      RECT 0.048 137.856 33.202 137.952 ;
      RECT 0.048 138.624 33.202 138.720 ;
      RECT 0.048 139.392 33.202 139.488 ;
      RECT 0.048 140.160 33.202 140.256 ;
      RECT 0.048 140.928 33.202 141.024 ;
      RECT 0.048 141.696 33.202 141.792 ;
      RECT 0.048 142.464 33.202 142.560 ;
      RECT 0.048 143.232 33.202 143.328 ;
      RECT 0.048 144.000 33.202 144.096 ;
      RECT 0.048 144.768 33.202 144.864 ;
      RECT 0.048 145.536 33.202 145.632 ;
      RECT 0.048 146.304 33.202 146.400 ;
      RECT 0.048 147.072 33.202 147.168 ;
      RECT 0.048 147.840 33.202 147.936 ;
      RECT 0.048 148.608 33.202 148.704 ;
      RECT 0.048 149.376 33.202 149.472 ;
      RECT 0.048 150.144 33.202 150.240 ;
      RECT 0.048 150.912 33.202 151.008 ;
      RECT 0.048 151.680 33.202 151.776 ;
      RECT 0.048 152.448 33.202 152.544 ;
      RECT 0.048 153.216 33.202 153.312 ;
      RECT 0.048 153.984 33.202 154.080 ;
      RECT 0.048 154.752 33.202 154.848 ;
      RECT 0.048 155.520 33.202 155.616 ;
      RECT 0.048 156.288 33.202 156.384 ;
      RECT 0.048 157.056 33.202 157.152 ;
      RECT 0.048 157.824 33.202 157.920 ;
      RECT 0.048 158.592 33.202 158.688 ;
      RECT 0.048 159.360 33.202 159.456 ;
      RECT 0.048 160.128 33.202 160.224 ;
      RECT 0.048 160.896 33.202 160.992 ;
      RECT 0.048 161.664 33.202 161.760 ;
      RECT 0.048 162.432 33.202 162.528 ;
      RECT 0.048 163.200 33.202 163.296 ;
      RECT 0.048 163.968 33.202 164.064 ;
      RECT 0.048 164.736 33.202 164.832 ;
      RECT 0.048 165.504 33.202 165.600 ;
      RECT 0.048 166.272 33.202 166.368 ;
    END
  END VDD
  OBS
    LAYER M1 ;
    RECT 0 0 33.250 166.600 ;
    LAYER M2 ;
    RECT 0 0 33.250 166.600 ;
    LAYER M3 ;
    RECT 0 0 33.250 166.600 ;
    LAYER M4 ;
    RECT 0 0 33.250 166.600 ;
  END
END fakeram7_sp_4096x32

END LIBRARY
